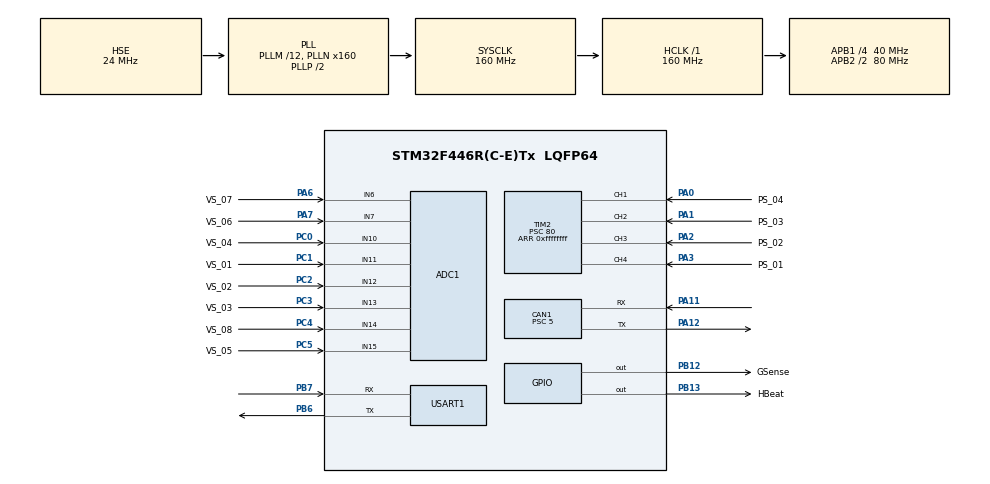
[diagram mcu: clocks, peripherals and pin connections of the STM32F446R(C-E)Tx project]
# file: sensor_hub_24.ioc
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ADC1.Channel-0\#ChannelRegularConversion=ADC_CHANNEL_10
ADC1.Channel-1\#ChannelRegularConversion=ADC_CHANNEL_11
ADC1.Channel-2\#ChannelRegularConversion=ADC_CHANNEL_12
ADC1.Channel-3\#ChannelRegularConversion=ADC_CHANNEL_13
ADC1.ContinuousConvMode=ENABLE
ADC1.DMAContinuousRequests=ENABLE
ADC1.InjNumberOfConversion=0
ADC1.NbrOfConversion=4
ADC1.NbrOfConversionFlag=1
ADC1.Rank-0\#ChannelRegularConversion=1
ADC1.Rank-1\#ChannelRegularConversion=2
ADC1.Rank-2\#ChannelRegularConversion=3
ADC1.Rank-3\#ChannelRegularConversion=4
ADC1.SamplingTime-0\#ChannelRegularConversion=ADC_SAMPLETIME_15CYCLES
ADC1.SamplingTime-1\#ChannelRegularConversion=ADC_SAMPLETIME_15CYCLES
ADC1.SamplingTime-2\#ChannelRegularConversion=ADC_SAMPLETIME_15CYCLES
ADC1.SamplingTime-3\#ChannelRegularConversion=ADC_SAMPLETIME_15CYCLES
ADC1.ScanConvMode=ENABLE
ADC1.master=1
CAN1.ABOM=ENABLE
CAN1.AWUM=ENABLE
CAN1.BS1=CAN_BS1_6TQ
CAN1.BS2=CAN_BS2_1TQ
CAN1.CalculateBaudRate=1000000
CAN1.CalculateTimeBit=1000
CAN1.CalculateTimeQuantum=125.0
CAN1.Mode=CAN_MODE_NORMAL
CAN1.Prescaler=5
Dma.ADC1.0.Direction=DMA_PERIPH_TO_MEMORY
Dma.ADC1.0.FIFOMode=DMA_FIFOMODE_DISABLE
Dma.ADC1.0.Instance=DMA2_Stream0
Dma.ADC1.0.MemDataAlignment=DMA_MDATAALIGN_HALFWORD
Dma.ADC1.0.MemInc=DMA_MINC_ENABLE
Dma.ADC1.0.Mode=DMA_CIRCULAR
Dma.ADC1.0.PeriphDataAlignment=DMA_PDATAALIGN_HALFWORD
Dma.ADC1.0.PeriphInc=DMA_PINC_DISABLE
Dma.ADC1.0.Priority=DMA_PRIORITY_LOW
Dma.Request0=ADC1
FREERTOS.Tasks01=main_task,0,512,task_MainTask,Default,NULL,Dynamic,NULL,NULL;buffer_handling,1,256,task_BufferHandling,Default,NULL,Dynamic,NULL,NULL
FREERTOS.configENABLE_FPU=1
FREERTOS.configMINIMAL_STACK_SIZE=256
Mcu.Family=STM32F4
Mcu.Name=STM32F446R(C-E)Tx
Mcu.Package=LQFP64
NVIC.CAN1_RX0_IRQn=true\:5\:0\:false\:false\:true\:true\:true\:true\:true
NVIC.CAN1_RX1_IRQn=true\:5\:0\:false\:false\:true\:true\:true\:true\:true
NVIC.CAN1_TX_IRQn=true\:5\:0\:false\:false\:true\:true\:true\:true\:true
NVIC.DMA2_Stream0_IRQn=true\:5\:0\:false\:false\:true\:true\:false\:true\:true
NVIC.PriorityGroup=NVIC_PRIORITYGROUP_4
NVIC.TIM1_UP_TIM10_IRQn=true\:5\:0\:false\:false\:true\:true\:true\:true\:true
NVIC.TIM6_DAC_IRQn=true\:15\:0\:false\:false\:true\:false\:false\:true\:true
NVIC.TimeBase=TIM6_DAC_IRQn
NVIC.TimeBaseIP=TIM6
PA0-WKUP.GPIO_Label=PS_04
PA0-WKUP.Signal=S_TIM2_CH1_ETR
PA1.GPIO_Label=PS_03
PA1.Signal=S_TIM2_CH2
PA11.Mode=CAN_Activate
PA11.Signal=CAN1_RX
PA12.Mode=CAN_Activate
PA12.Signal=CAN1_TX
PA2.GPIO_Label=PS_02
PA2.Signal=S_TIM2_CH3
PA3.GPIO_Label=PS_01
PA3.Signal=S_TIM2_CH4
PA6.GPIO_Label=VS_07
PA6.Signal=ADCx_IN6
PA7.GPIO_Label=VS_06
PA7.Signal=ADCx_IN7
PB12.GPIO_Label=GSense
PB12.Signal=GPIO_Output
PB13.GPIO_Label=HBeat
PB13.Signal=GPIO_Output
PB6.Mode=Asynchronous
PB6.Signal=USART1_TX
PB7.Mode=Asynchronous
PB7.Signal=USART1_RX
PC0.GPIO_Label=VS_04
PC0.Signal=ADCx_IN10
PC1.GPIO_Label=VS_01
PC1.Signal=ADCx_IN11
PC2.GPIO_Label=VS_02
PC2.Signal=ADCx_IN12
PC3.GPIO_Label=VS_03
PC3.Signal=ADCx_IN13
PC4.GPIO_Label=VS_08
PC4.Signal=ADCx_IN14
PC5.GPIO_Label=VS_05
PC5.Signal=ADCx_IN15
PH0-OSC_IN.Mode=HSE-External-Clock-Source
PH0-OSC_IN.Signal=RCC_OSC_IN
PH1-OSC_OUT.Mode=HSE-External-Clock-Source
PH1-OSC_OUT.Signal=RCC_OSC_OUT
ProjectManager.HeapSize=0x200
ProjectManager.StackSize=0x400
ProjectManager.TargetToolchain=STM32CubeIDE
RCC.AHBFreq_Value=160000000
RCC.APB1CLKDivider=RCC_HCLK_DIV4
RCC.APB1Freq_Value=40000000
RCC.APB1TimFreq_Value=80000000
RCC.APB2CLKDivider=RCC_HCLK_DIV2
RCC.APB2Freq_Value=80000000
RCC.APB2TimFreq_Value=160000000
RCC.CortexFreq_Value=160000000
RCC.HCLKFreq_Value=160000000
RCC.HSE_VALUE=24000000
RCC.PLLM=12
RCC.PLLN=160
RCC.PLLSourceVirtual=RCC_PLLSOURCE_HSE
RCC.SYSCLKFreq_VALUE=160000000
RCC.SYSCLKSource=RCC_SYSCLKSOURCE_PLLCLK
RCC.USBFreq_Value=160000000
RCC.VCOOutputFreq_Value=320000000
SH.ADCx_IN10.0=ADC1_IN10,IN10
SH.ADCx_IN11.0=ADC1_IN11,IN11
SH.ADCx_IN12.0=ADC1_IN12,IN12
SH.ADCx_IN13.0=ADC1_IN13,IN13
SH.ADCx_IN14.0=ADC1_IN14,IN14
SH.ADCx_IN15.0=ADC1_IN15,IN15
SH.ADCx_IN6.0=ADC1_IN6,IN6
SH.ADCx_IN7.0=ADC1_IN7,IN7
SH.S_TIM2_CH1_ETR.0=TIM2_CH1,Input_Capture1_from_TI1
SH.S_TIM2_CH2.0=TIM2_CH2,Input_Capture2_from_TI2
SH.S_TIM2_CH3.0=TIM2_CH3,Input_Capture3_from_TI3
SH.S_TIM2_CH4.0=TIM2_CH4,Input_Capture4_from_TI4
TIM2.Channel-Input_Capture1_from_TI1=TIM_CHANNEL_1
TIM2.Channel-Input_Capture2_from_TI2=TIM_CHANNEL_2
TIM2.Channel-Input_Capture3_from_TI3=TIM_CHANNEL_3
TIM2.Channel-Input_Capture4_from_TI4=TIM_CHANNEL_4
TIM2.Period=0xffffffff
TIM2.Prescaler=80
USART1.VirtualMode=VM_ASYNC
VP_FREERTOS_VS_CMSIS_V1.Mode=CMSIS_V1
VP_SYS_VS_tim6.Mode=TIM6
VP_TIM10_VS_ClockSourceINT.Mode=Enable_Timer
VP_TIM2_VS_ClockSourceINT.Mode=Internal
board=custom

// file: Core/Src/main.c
/* USER CODE BEGIN Header */
/**
  ******************************************************************************
  * @file           : main.c
  * @brief          : Main program body
  ******************************************************************************
  * @attention
  *
  * Copyright (c) 2022 STMicroelectronics.
  * All rights reserved.
  *
  * This software is licensed under terms that can be found in the LICENSE file
  * in the root directory of this software component.
  * If no LICENSE file comes with this software, it is provided AS-IS.
  *
  ******************************************************************************
  */
/* USER CODE END Header */
#include "main.h"
#include "cmsis_os.h"

/* USER CODE BEGIN Includes */
#include "GopherCAN_devboard_example.h"
#include "gopher_sense.h"

/* USER CODE END Includes */

ADC_HandleTypeDef hadc1;
DMA_HandleTypeDef hdma_adc1;

CAN_HandleTypeDef hcan1;

TIM_HandleTypeDef htim2;
TIM_HandleTypeDef htim10;

UART_HandleTypeDef huart1;

osThreadId main_taskHandle;
osThreadId buffer_handlingHandle;

void SystemClock_Config(void);
static void MX_GPIO_Init(void);
static void MX_DMA_Init(void);
static void MX_CAN1_Init(void);
static void MX_ADC1_Init(void);
static void MX_TIM10_Init(void);
static void MX_USART1_UART_Init(void);
static void MX_TIM2_Init(void);
void task_MainTask(void const * argument);
void task_BufferHandling(void const * argument);

/* USER CODE BEGIN 0 */
#ifdef __GNUC__
#define PUTCHAR_PROTOTYPE int __io_putchar(int ch)
#else
#define PUTCHAR_PROTOTYPE int fputc(int ch, FILE *f)
#endif

PUTCHAR_PROTOTYPE
{
  HAL_UART_Transmit(&huart1, (uint8_t *)&ch, 1, HAL_MAX_DELAY);
  return ch;
}
/* USER CODE END 0 */

int main(void)
{

  /* MCU Configuration--------------------------------------------------------*/

  /* Reset of all peripherals, Initializes the Flash interface and the Systick. */
  HAL_Init();

  /* Configure the system clock */
  SystemClock_Config();

  /* Initialize all configured peripherals */
  MX_GPIO_Init();
  MX_DMA_Init();
  MX_CAN1_Init();
  MX_ADC1_Init();
  MX_TIM10_Init();
  MX_USART1_UART_Init();
  MX_TIM2_Init();
  /* USER CODE BEGIN 2 */

  init(&hcan1);
  gsense_init(&hcan1, &hadc1, NULL, NULL, &htim10,
		  GSense_GPIO_Port, GSense_Pin);
  // TODO init speed sensors

  set_all_param_sending(TRUE);

  UNSIGNED8 state = 0;

  HAL_GPIO_WritePin(Pullup_1_GPIO_Port, Pullup_1_Pin, state);
  HAL_GPIO_WritePin(Pullup_2_GPIO_Port, Pullup_2_Pin, state);
  HAL_GPIO_WritePin(Pullup_3_GPIO_Port, Pullup_3_Pin, state);
  HAL_GPIO_WritePin(Pullup_4_GPIO_Port, Pullup_4_Pin, state);

  /* USER CODE END 2 */

  /* Create the thread(s) */
  /* definition and creation of main_task */
  osThreadDef(main_task, task_MainTask, osPriorityNormal, 0, 512);
  main_taskHandle = osThreadCreate(osThread(main_task), NULL);

  /* definition and creation of buffer_handling */
  osThreadDef(buffer_handling, task_BufferHandling, osPriorityAboveNormal, 0, 256);
  buffer_handlingHandle = osThreadCreate(osThread(buffer_handling), NULL);

  /* Start scheduler */
  osKernelStart();

  /* We should never get here as control is now taken by the scheduler */
  /* Infinite loop */
  while (1)
  {

  }
}

void SystemClock_Config(void)
{
  RCC_OscInitTypeDef RCC_OscInitStruct = {0};
  RCC_ClkInitTypeDef RCC_ClkInitStruct = {0};

  /** Configure the main internal regulator output voltage
  */
  __HAL_RCC_PWR_CLK_ENABLE();
  __HAL_PWR_VOLTAGESCALING_CONFIG(PWR_REGULATOR_VOLTAGE_SCALE1);

  /** Initializes the RCC Oscillators according to the specified parameters
  * in the RCC_OscInitTypeDef structure.
  */
  RCC_OscInitStruct.OscillatorType = RCC_OSCILLATORTYPE_HSE;
  RCC_OscInitStruct.HSEState = RCC_HSE_BYPASS;
  RCC_OscInitStruct.PLL.PLLState = RCC_PLL_ON;
  RCC_OscInitStruct.PLL.PLLSource = RCC_PLLSOURCE_HSE;
  RCC_OscInitStruct.PLL.PLLM = 12;
  RCC_OscInitStruct.PLL.PLLN = 160;
  RCC_OscInitStruct.PLL.PLLP = RCC_PLLP_DIV2;
  RCC_OscInitStruct.PLL.PLLQ = 2;
  RCC_OscInitStruct.PLL.PLLR = 2;
  if (HAL_RCC_OscConfig(&RCC_OscInitStruct) != HAL_OK)
  {
    Error_Handler();
  }

  /** Initializes the CPU, AHB and APB buses clocks
  */
  RCC_ClkInitStruct.ClockType = RCC_CLOCKTYPE_HCLK|RCC_CLOCKTYPE_SYSCLK
                              |RCC_CLOCKTYPE_PCLK1|RCC_CLOCKTYPE_PCLK2;
  RCC_ClkInitStruct.SYSCLKSource = RCC_SYSCLKSOURCE_PLLCLK;
  RCC_ClkInitStruct.AHBCLKDivider = RCC_SYSCLK_DIV1;
  RCC_ClkInitStruct.APB1CLKDivider = RCC_HCLK_DIV4;
  RCC_ClkInitStruct.APB2CLKDivider = RCC_HCLK_DIV2;

  if (HAL_RCC_ClockConfig(&RCC_ClkInitStruct, FLASH_LATENCY_5) != HAL_OK)
  {
    Error_Handler();
  }
}

static void MX_ADC1_Init(void)
{

  ADC_ChannelConfTypeDef sConfig = {0};

  /** Configure the global features of the ADC (Clock, Resolution, Data Alignment and number of conversion)
  */
  hadc1.Instance = ADC1;
  hadc1.Init.ClockPrescaler = ADC_CLOCK_SYNC_PCLK_DIV4;
  hadc1.Init.Resolution = ADC_RESOLUTION_12B;
  hadc1.Init.ScanConvMode = ENABLE;
  hadc1.Init.ContinuousConvMode = ENABLE;
  hadc1.Init.DiscontinuousConvMode = DISABLE;
  hadc1.Init.ExternalTrigConvEdge = ADC_EXTERNALTRIGCONVEDGE_NONE;
  hadc1.Init.ExternalTrigConv = ADC_SOFTWARE_START;
  hadc1.Init.DataAlign = ADC_DATAALIGN_RIGHT;
  hadc1.Init.NbrOfConversion = 12;
  hadc1.Init.DMAContinuousRequests = ENABLE;
  hadc1.Init.EOCSelection = ADC_EOC_SINGLE_CONV;
  if (HAL_ADC_Init(&hadc1) != HAL_OK)
  {
    Error_Handler();
  }

  /** Configure for the selected ADC regular channel its corresponding rank in the sequencer and its sample time.
  */
  sConfig.Channel = ADC_CHANNEL_4;
  sConfig.Rank = 1;
  sConfig.SamplingTime = ADC_SAMPLETIME_480CYCLES;
  if (HAL_ADC_ConfigChannel(&hadc1, &sConfig) != HAL_OK)
  {
    Error_Handler();
  }

  /** Configure for the selected ADC regular channel its corresponding rank in the sequencer and its sample time.
  */
  sConfig.Channel = ADC_CHANNEL_5;
  sConfig.Rank = 2;
  if (HAL_ADC_ConfigChannel(&hadc1, &sConfig) != HAL_OK)
  {
    Error_Handler();
  }

  /** Configure for the selected ADC regular channel its corresponding rank in the sequencer and its sample time.
  */
  sConfig.Channel = ADC_CHANNEL_6;
  sConfig.Rank = 3;
  if (HAL_ADC_ConfigChannel(&hadc1, &sConfig) != HAL_OK)
  {
    Error_Handler();
  }

  /** Configure for the selected ADC regular channel its corresponding rank in the sequencer and its sample time.
  */
  sConfig.Channel = ADC_CHANNEL_7;
  sConfig.Rank = 4;
  if (HAL_ADC_ConfigChannel(&hadc1, &sConfig) != HAL_OK)
  {
    Error_Handler();
  }

  /** Configure for the selected ADC regular channel its corresponding rank in the sequencer and its sample time.
  */
  sConfig.Channel = ADC_CHANNEL_8;
  sConfig.Rank = 5;
  if (HAL_ADC_ConfigChannel(&hadc1, &sConfig) != HAL_OK)
  {
    Error_Handler();
  }

  /** Configure for the selected ADC regular channel its corresponding rank in the sequencer and its sample time.
  */
  sConfig.Channel = ADC_CHANNEL_9;
  sConfig.Rank = 6;
  if (HAL_ADC_ConfigChannel(&hadc1, &sConfig) != HAL_OK)
  {
    Error_Handler();
  }

  /** Configure for the selected ADC regular channel its corresponding rank in the sequencer and its sample time.
  */
  sConfig.Channel = ADC_CHANNEL_10;
  sConfig.Rank = 7;
  if (HAL_ADC_ConfigChannel(&hadc1, &sConfig) != HAL_OK)
  {
    Error_Handler();
  }

  /** Configure for the selected ADC regular channel its corresponding rank in the sequencer and its sample time.
  */
  sConfig.Channel = ADC_CHANNEL_11;
  sConfig.Rank = 8;
  if (HAL_ADC_ConfigChannel(&hadc1, &sConfig) != HAL_OK)
  {
    Error_Handler();
  }

  /** Configure for the selected ADC regular channel its corresponding rank in the sequencer and its sample time.
  */
  sConfig.Channel = ADC_CHANNEL_12;
  sConfig.Rank = 9;
  if (HAL_ADC_ConfigChannel(&hadc1, &sConfig) != HAL_OK)
  {
    Error_Handler();
  }

  /** Configure for the selected ADC regular channel its corresponding rank in the sequencer and its sample time.
  */
  sConfig.Channel = ADC_CHANNEL_13;
  sConfig.Rank = 10;
  if (HAL_ADC_ConfigChannel(&hadc1, &sConfig) != HAL_OK)
  {
    Error_Handler();
  }

  /** Configure for the selected ADC regular channel its corresponding rank in the sequencer and its sample time.
  */
  sConfig.Channel = ADC_CHANNEL_14;
  sConfig.Rank = 11;
  if (HAL_ADC_ConfigChannel(&hadc1, &sConfig) != HAL_OK)
  {
    Error_Handler();
  }

  /** Configure for the selected ADC regular channel its corresponding rank in the sequencer and its sample time.
  */
  sConfig.Channel = ADC_CHANNEL_15;
  sConfig.Rank = 12;
  if (HAL_ADC_ConfigChannel(&hadc1, &sConfig) != HAL_OK)
  {
    Error_Handler();
  }

}

static void MX_CAN1_Init(void)
{

  hcan1.Instance = CAN1;
  hcan1.Init.Prescaler = 5;
  hcan1.Init.Mode = CAN_MODE_NORMAL;
  hcan1.Init.SyncJumpWidth = CAN_SJW_1TQ;
  hcan1.Init.TimeSeg1 = CAN_BS1_6TQ;
  hcan1.Init.TimeSeg2 = CAN_BS2_1TQ;
  hcan1.Init.TimeTriggeredMode = DISABLE;
  hcan1.Init.AutoBusOff = ENABLE;
  hcan1.Init.AutoWakeUp = ENABLE;
  hcan1.Init.AutoRetransmission = DISABLE;
  hcan1.Init.ReceiveFifoLocked = DISABLE;
  hcan1.Init.TransmitFifoPriority = DISABLE;
  if (HAL_CAN_Init(&hcan1) != HAL_OK)
  {
    Error_Handler();
  }

}

static void MX_TIM2_Init(void)
{

  TIM_ClockConfigTypeDef sClockSourceConfig = {0};
  TIM_MasterConfigTypeDef sMasterConfig = {0};
  TIM_IC_InitTypeDef sConfigIC = {0};

  htim2.Instance = TIM2;
  htim2.Init.Prescaler = 80;
  htim2.Init.CounterMode = TIM_COUNTERMODE_UP;
  htim2.Init.Period = 0xffffffff;
  htim2.Init.ClockDivision = TIM_CLOCKDIVISION_DIV1;
  htim2.Init.AutoReloadPreload = TIM_AUTORELOAD_PRELOAD_DISABLE;
  if (HAL_TIM_Base_Init(&htim2) != HAL_OK)
  {
    Error_Handler();
  }
  sClockSourceConfig.ClockSource = TIM_CLOCKSOURCE_INTERNAL;
  if (HAL_TIM_ConfigClockSource(&htim2, &sClockSourceConfig) != HAL_OK)
  {
    Error_Handler();
  }
  if (HAL_TIM_IC_Init(&htim2) != HAL_OK)
  {
    Error_Handler();
  }
  sMasterConfig.MasterOutputTrigger = TIM_TRGO_RESET;
  sMasterConfig.MasterSlaveMode = TIM_MASTERSLAVEMODE_DISABLE;
  if (HAL_TIMEx_MasterConfigSynchronization(&htim2, &sMasterConfig) != HAL_OK)
  {
    Error_Handler();
  }
  sConfigIC.ICPolarity = TIM_INPUTCHANNELPOLARITY_RISING;
  sConfigIC.ICSelection = TIM_ICSELECTION_DIRECTTI;
  sConfigIC.ICPrescaler = TIM_ICPSC_DIV1;
  sConfigIC.ICFilter = 0;
  if (HAL_TIM_IC_ConfigChannel(&htim2, &sConfigIC, TIM_CHANNEL_1) != HAL_OK)
  {
    Error_Handler();
  }
  if (HAL_TIM_IC_ConfigChannel(&htim2, &sConfigIC, TIM_CHANNEL_2) != HAL_OK)
  {
    Error_Handler();
  }
  if (HAL_TIM_IC_ConfigChannel(&htim2, &sConfigIC, TIM_CHANNEL_3) != HAL_OK)
  {
    Error_Handler();
  }
  if (HAL_TIM_IC_ConfigChannel(&htim2, &sConfigIC, TIM_CHANNEL_4) != HAL_OK)
  {
    Error_Handler();
  }

}

static void MX_TIM10_Init(void)
{

  htim10.Instance = TIM10;
  htim10.Init.Prescaler = 0;
  htim10.Init.CounterMode = TIM_COUNTERMODE_UP;
  htim10.Init.Period = 65535;
  htim10.Init.ClockDivision = TIM_CLOCKDIVISION_DIV1;
  htim10.Init.AutoReloadPreload = TIM_AUTORELOAD_PRELOAD_DISABLE;
  if (HAL_TIM_Base_Init(&htim10) != HAL_OK)
  {
    Error_Handler();
  }

}

static void MX_USART1_UART_Init(void)
{

  huart1.Instance = USART1;
  huart1.Init.BaudRate = 115200;
  huart1.Init.WordLength = UART_WORDLENGTH_8B;
  huart1.Init.StopBits = UART_STOPBITS_1;
  huart1.Init.Parity = UART_PARITY_NONE;
  huart1.Init.Mode = UART_MODE_TX_RX;
  huart1.Init.HwFlowCtl = UART_HWCONTROL_NONE;
  huart1.Init.OverSampling = UART_OVERSAMPLING_16;
  if (HAL_UART_Init(&huart1) != HAL_OK)
  {
    Error_Handler();
  }

}

static void MX_DMA_Init(void)
{

  /* DMA controller clock enable */
  __HAL_RCC_DMA2_CLK_ENABLE();

  /* DMA interrupt init */
  /* DMA2_Stream0_IRQn interrupt configuration */
  HAL_NVIC_SetPriority(DMA2_Stream0_IRQn, 5, 0);
  HAL_NVIC_EnableIRQ(DMA2_Stream0_IRQn);

}

static void MX_GPIO_Init(void)
{
  GPIO_InitTypeDef GPIO_InitStruct = {0};

  /* GPIO Ports Clock Enable */
  __HAL_RCC_GPIOC_CLK_ENABLE();
  __HAL_RCC_GPIOH_CLK_ENABLE();
  __HAL_RCC_GPIOA_CLK_ENABLE();
  __HAL_RCC_GPIOB_CLK_ENABLE();
  __HAL_RCC_GPIOD_CLK_ENABLE();

  /*Configure GPIO pin Output Level */
  HAL_GPIO_WritePin(GPIOC, Pullup_1_Pin|Pullup_2_Pin|Pullup_3_Pin|PU10_Pin
                          |PU9_Pin|PU8_Pin|PU7_Pin, GPIO_PIN_RESET);

  /*Configure GPIO pin Output Level */
  HAL_GPIO_WritePin(GPIOB, GSense_Pin|HBeat_Pin|PU12_Pin|PU11_Pin
                          |Pu5_Pin|PU4_Pin, GPIO_PIN_RESET);

  /*Configure GPIO pin Output Level */
  HAL_GPIO_WritePin(PU6_GPIO_Port, PU6_Pin, GPIO_PIN_RESET);

  /*Configure GPIO pins : Pullup_1_Pin Pullup_2_Pin Pullup_3_Pin PU10_Pin
                           PU9_Pin PU8_Pin PU7_Pin */
  GPIO_InitStruct.Pin = Pullup_1_Pin|Pullup_2_Pin|Pullup_3_Pin|PU10_Pin
                          |PU9_Pin|PU8_Pin|PU7_Pin;
  GPIO_InitStruct.Mode = GPIO_MODE_OUTPUT_PP;
  GPIO_InitStruct.Pull = GPIO_NOPULL;
  GPIO_InitStruct.Speed = GPIO_SPEED_FREQ_LOW;
  HAL_GPIO_Init(GPIOC, &GPIO_InitStruct);

  /*Configure GPIO pins : GSense_Pin HBeat_Pin PU12_Pin PU11_Pin
                           Pu5_Pin PU4_Pin */
  GPIO_InitStruct.Pin = GSense_Pin|HBeat_Pin|PU12_Pin|PU11_Pin
                          |Pu5_Pin|PU4_Pin;
  GPIO_InitStruct.Mode = GPIO_MODE_OUTPUT_PP;
  GPIO_InitStruct.Pull = GPIO_NOPULL;
  GPIO_InitStruct.Speed = GPIO_SPEED_FREQ_LOW;
  HAL_GPIO_Init(GPIOB, &GPIO_InitStruct);

  /*Configure GPIO pin : PU6_Pin */
  GPIO_InitStruct.Pin = PU6_Pin;
  GPIO_InitStruct.Mode = GPIO_MODE_OUTPUT_PP;
  GPIO_InitStruct.Pull = GPIO_NOPULL;
  GPIO_InitStruct.Speed = GPIO_SPEED_FREQ_LOW;
  HAL_GPIO_Init(PU6_GPIO_Port, &GPIO_InitStruct);

  /*Configure GPIO pin : MCU_3v3_Swithc_Fault_Pin */
  GPIO_InitStruct.Pin = MCU_3v3_Swithc_Fault_Pin;
  GPIO_InitStruct.Mode = GPIO_MODE_INPUT;
  GPIO_InitStruct.Pull = GPIO_NOPULL;
  HAL_GPIO_Init(MCU_3v3_Swithc_Fault_GPIO_Port, &GPIO_InitStruct);

}

void task_MainTask(void const * argument)
{
  /* USER CODE BEGIN 5 */
  /* Infinite loop */
  for(;;)
  {
	  main_loop();
    osDelay(10);
  }
  /* USER CODE END 5 */
}

void task_BufferHandling(void const * argument)
{
  /* USER CODE BEGIN task_BufferHandling */
  /* Infinite loop */
  for(;;)
  {
	  can_buffer_handling_loop();
    osDelay(1);
  }
  /* USER CODE END task_BufferHandling */
}

void HAL_TIM_PeriodElapsedCallback(TIM_HandleTypeDef *htim)
{
  if (htim->Instance == TIM6) {
    HAL_IncTick();
  }
  /* USER CODE BEGIN Callback 1 */
  else
  {
	  DAQ_TimerCallback(htim);
  }
  /* USER CODE END Callback 1 */
}

void Error_Handler(void)
{
  __disable_irq();
  while (1)
  {
  }
}
